VERSION 5.8 ;
BUSBITCHARS "[]" ;
DIVIDERCHAR "/" ;
UNITS DISTANCE MICRONS 2000 ;

# Standard Cell Library - Base AT (Advanced Threshold)
# Technology: tcbn07 (7nm node), BWP300H8P64PD (Back-end), LVT (Low Vt)

# Inverter
MACRO INVX1BWP300H8P64PDLVT
  CLASS CORE ;
  ORIGIN 0.0 0.0 ;
  SIZE 0.3 BY 0.3 ;
  SYMMETRY X Y ;
  PIN A
    DIRECTION INPUT ;
    USE SIGNAL ;
    PORT
      LAYER M1 ;
      RECT 0.0 0.1 0.1 0.2 ;
    END
  END A
  PIN Y
    DIRECTION OUTPUT ;
    USE SIGNAL ;
    PORT
      LAYER M1 ;
      RECT 0.2 0.1 0.3 0.2 ;
    END
  END Y
END INVX1BWP300H8P64PDLVT

# Buffers
MACRO BUFFD1BWP300H8P64PDLVT
  CLASS CORE ;
  ORIGIN 0.0 0.0 ;
  SIZE 0.45 BY 0.3 ;
  SYMMETRY X Y ;
  PIN A
    DIRECTION INPUT ;
    USE SIGNAL ;
    PORT
      LAYER M1 ;
      RECT 0.0 0.1 0.1 0.2 ;
    END
  END A
  PIN Y
    DIRECTION OUTPUT ;
    USE SIGNAL ;
    PORT
      LAYER M1 ;
      RECT 0.35 0.1 0.45 0.2 ;
    END
  END Y
END BUFFD1BWP300H8P64PDLVT

MACRO BUFFD2BWP300H8P64PDLVT
  CLASS CORE ;
  ORIGIN 0.0 0.0 ;
  SIZE 0.6 BY 0.3 ;
  SYMMETRY X Y ;
  PIN A
    DIRECTION INPUT ;
    USE SIGNAL ;
    PORT
      LAYER M1 ;
      RECT 0.0 0.1 0.1 0.2 ;
    END
  END A
  PIN Y
    DIRECTION OUTPUT ;
    USE SIGNAL ;
    PORT
      LAYER M1 ;
      RECT 0.5 0.1 0.6 0.2 ;
    END
  END Y
END BUFFD2BWP300H8P64PDLVT

MACRO BUFFD3BWP300H8P64PDLVT
  CLASS CORE ;
  ORIGIN 0.0 0.0 ;
  SIZE 0.75 BY 0.3 ;
  SYMMETRY X Y ;
  PIN A
    DIRECTION INPUT ;
    USE SIGNAL ;
    PORT
      LAYER M1 ;
      RECT 0.0 0.1 0.1 0.2 ;
    END
  END A
  PIN Y
    DIRECTION OUTPUT ;
    USE SIGNAL ;
    PORT
      LAYER M1 ;
      RECT 0.65 0.1 0.75 0.2 ;
    END
  END Y
END BUFFD3BWP300H8P64PDLVT

MACRO BUFFD4BWP300H8P64PDLVT
  CLASS CORE ;
  ORIGIN 0.0 0.0 ;
  SIZE 0.9 BY 0.3 ;
  SYMMETRY X Y ;
  PIN A
    DIRECTION INPUT ;
    USE SIGNAL ;
    PORT
      LAYER M1 ;
      RECT 0.0 0.1 0.1 0.2 ;
    END
  END A
  PIN Y
    DIRECTION OUTPUT ;
    USE SIGNAL ;
    PORT
      LAYER M1 ;
      RECT 0.8 0.1 0.9 0.2 ;
    END
  END Y
END BUFFD4BWP300H8P64PDLVT

MACRO BUFFD6BWP300H8P64PDLVT
  CLASS CORE ;
  ORIGIN 0.0 0.0 ;
  SIZE 1.2 BY 0.3 ;
  SYMMETRY X Y ;
  PIN A
    DIRECTION INPUT ;
    USE SIGNAL ;
    PORT
      LAYER M1 ;
      RECT 0.0 0.1 0.1 0.2 ;
    END
  END A
  PIN Y
    DIRECTION OUTPUT ;
    USE SIGNAL ;
    PORT
      LAYER M1 ;
      RECT 1.1 0.1 1.2 0.2 ;
    END
  END Y
END BUFFD6BWP300H8P64PDLVT

MACRO BUFFD8BWP300H8P64PDLVT
  CLASS CORE ;
  ORIGIN 0.0 0.0 ;
  SIZE 1.5 BY 0.3 ;
  SYMMETRY X Y ;
  PIN A
    DIRECTION INPUT ;
    USE SIGNAL ;
    PORT
      LAYER M1 ;
      RECT 0.0 0.1 0.1 0.2 ;
    END
  END A
  PIN Y
    DIRECTION OUTPUT ;
    USE SIGNAL ;
    PORT
      LAYER M1 ;
      RECT 1.4 0.1 1.5 0.2 ;
    END
  END Y
END BUFFD8BWP300H8P64PDLVT

# AND gates
MACRO AN2D1BWP300H8P64PDLVT
  CLASS CORE ;
  ORIGIN 0.0 0.0 ;
  SIZE 0.45 BY 0.3 ;
  SYMMETRY X Y ;
  PIN A
    DIRECTION INPUT ;
    USE SIGNAL ;
    PORT
      LAYER M1 ;
      RECT 0.0 0.1 0.1 0.2 ;
    END
  END A
  PIN B
    DIRECTION INPUT ;
    USE SIGNAL ;
    PORT
      LAYER M1 ;
      RECT 0.15 0.1 0.25 0.2 ;
    END
  END B
  PIN Y
    DIRECTION OUTPUT ;
    USE SIGNAL ;
    PORT
      LAYER M1 ;
      RECT 0.35 0.1 0.45 0.2 ;
    END
  END Y
END AN2D1BWP300H8P64PDLVT

MACRO AN2D2BWP300H8P64PDLVT
  CLASS CORE ;
  ORIGIN 0.0 0.0 ;
  SIZE 0.45 BY 0.3 ;
  SYMMETRY X Y ;
  PIN A
    DIRECTION INPUT ;
    USE SIGNAL ;
    PORT
      LAYER M1 ;
      RECT 0.0 0.1 0.1 0.2 ;
    END
  END A
  PIN B
    DIRECTION INPUT ;
    USE SIGNAL ;
    PORT
      LAYER M1 ;
      RECT 0.15 0.1 0.25 0.2 ;
    END
  END B
  PIN Y
    DIRECTION OUTPUT ;
    USE SIGNAL ;
    PORT
      LAYER M1 ;
      RECT 0.35 0.1 0.45 0.2 ;
    END
  END Y
END AN2D2BWP300H8P64PDLVT

MACRO AN2D3BWP300H8P64PDLVT
  CLASS CORE ;
  ORIGIN 0.0 0.0 ;
  SIZE 0.45 BY 0.3 ;
  SYMMETRY X Y ;
  PIN A
    DIRECTION INPUT ;
    USE SIGNAL ;
    PORT
      LAYER M1 ;
      RECT 0.0 0.1 0.1 0.2 ;
    END
  END A
  PIN B
    DIRECTION INPUT ;
    USE SIGNAL ;
    PORT
      LAYER M1 ;
      RECT 0.15 0.1 0.25 0.2 ;
    END
  END B
  PIN Y
    DIRECTION OUTPUT ;
    USE SIGNAL ;
    PORT
      LAYER M1 ;
      RECT 0.35 0.1 0.45 0.2 ;
    END
  END Y
END AN2D3BWP300H8P64PDLVT

MACRO AN2D4BWP300H8P64PDLVT
  CLASS CORE ;
  ORIGIN 0.0 0.0 ;
  SIZE 0.6 BY 0.3 ;
  SYMMETRY X Y ;
  PIN A
    DIRECTION INPUT ;
    USE SIGNAL ;
    PORT
      LAYER M1 ;
      RECT 0.0 0.1 0.1 0.2 ;
    END
  END A
  PIN B
    DIRECTION INPUT ;
    USE SIGNAL ;
    PORT
      LAYER M1 ;
      RECT 0.2 0.1 0.3 0.2 ;
    END
  END B
  PIN Y
    DIRECTION OUTPUT ;
    USE SIGNAL ;
    PORT
      LAYER M1 ;
      RECT 0.45 0.1 0.6 0.2 ;
    END
  END Y
END AN2D4BWP300H8P64PDLVT

# OR gates
MACRO OR2D1BWP300H8P64PDLVT
  CLASS CORE ;
  ORIGIN 0.0 0.0 ;
  SIZE 0.45 BY 0.3 ;
  SYMMETRY X Y ;
  PIN A
    DIRECTION INPUT ;
    USE SIGNAL ;
    PORT
      LAYER M1 ;
      RECT 0.0 0.1 0.1 0.2 ;
    END
  END A
  PIN B
    DIRECTION INPUT ;
    USE SIGNAL ;
    PORT
      LAYER M1 ;
      RECT 0.15 0.1 0.25 0.2 ;
    END
  END B
  PIN Y
    DIRECTION OUTPUT ;
    USE SIGNAL ;
    PORT
      LAYER M1 ;
      RECT 0.35 0.1 0.45 0.2 ;
    END
  END Y
END OR2D1BWP300H8P64PDLVT

MACRO OR2D2BWP300H8P64PDLVT
  CLASS CORE ;
  ORIGIN 0.0 0.0 ;
  SIZE 0.45 BY 0.3 ;
  SYMMETRY X Y ;
  PIN A
    DIRECTION INPUT ;
    USE SIGNAL ;
    PORT
      LAYER M1 ;
      RECT 0.0 0.1 0.1 0.2 ;
    END
  END A
  PIN B
    DIRECTION INPUT ;
    USE SIGNAL ;
    PORT
      LAYER M1 ;
      RECT 0.15 0.1 0.25 0.2 ;
    END
  END B
  PIN Y
    DIRECTION OUTPUT ;
    USE SIGNAL ;
    PORT
      LAYER M1 ;
      RECT 0.35 0.1 0.45 0.2 ;
    END
  END Y
END OR2D2BWP300H8P64PDLVT

# NAND gates
MACRO NAND2D1BWP300H8P64PDLVT
  CLASS CORE ;
  ORIGIN 0.0 0.0 ;
  SIZE 0.45 BY 0.3 ;
  SYMMETRY X Y ;
  PIN A
    DIRECTION INPUT ;
    USE SIGNAL ;
    PORT
      LAYER M1 ;
      RECT 0.0 0.1 0.1 0.2 ;
    END
  END A
  PIN B
    DIRECTION INPUT ;
    USE SIGNAL ;
    PORT
      LAYER M1 ;
      RECT 0.15 0.1 0.25 0.2 ;
    END
  END B
  PIN Y
    DIRECTION OUTPUT ;
    USE SIGNAL ;
    PORT
      LAYER M1 ;
      RECT 0.35 0.1 0.45 0.2 ;
    END
  END Y
END NAND2D1BWP300H8P64PDLVT

# NOR gates
MACRO NOR2D1BWP300H8P64PDLVT
  CLASS CORE ;
  ORIGIN 0.0 0.0 ;
  SIZE 0.45 BY 0.3 ;
  SYMMETRY X Y ;
  PIN A
    DIRECTION INPUT ;
    USE SIGNAL ;
    PORT
      LAYER M1 ;
      RECT 0.0 0.1 0.1 0.2 ;
    END
  END A
  PIN B
    DIRECTION INPUT ;
    USE SIGNAL ;
    PORT
      LAYER M1 ;
      RECT 0.15 0.1 0.25 0.2 ;
    END
  END B
  PIN Y
    DIRECTION OUTPUT ;
    USE SIGNAL ;
    PORT
      LAYER M1 ;
      RECT 0.35 0.1 0.45 0.2 ;
    END
  END Y
END NOR2D1BWP300H8P64PDLVT

# XOR gates
MACRO XOR2D1BWP300H8P64PDLVT
  CLASS CORE ;
  ORIGIN 0.0 0.0 ;
  SIZE 0.45 BY 0.3 ;
  SYMMETRY X Y ;
  PIN A
    DIRECTION INPUT ;
    USE SIGNAL ;
    PORT
      LAYER M1 ;
      RECT 0.0 0.1 0.1 0.2 ;
    END
  END A
  PIN B
    DIRECTION INPUT ;
    USE SIGNAL ;
    PORT
      LAYER M1 ;
      RECT 0.15 0.1 0.25 0.2 ;
    END
  END B
  PIN Y
    DIRECTION OUTPUT ;
    USE SIGNAL ;
    PORT
      LAYER M1 ;
      RECT 0.35 0.1 0.45 0.2 ;
    END
  END Y
END XOR2D1BWP300H8P64PDLVT

# 3-input gates
MACRO AN3D1BWP300H8P64PDLVT
  CLASS CORE ;
  ORIGIN 0.0 0.0 ;
  SIZE 0.6 BY 0.3 ;
  SYMMETRY X Y ;
  PIN A
    DIRECTION INPUT ;
    USE SIGNAL ;
    PORT
      LAYER M1 ;
      RECT 0.0 0.1 0.1 0.2 ;
    END
  END A
  PIN B
    DIRECTION INPUT ;
    USE SIGNAL ;
    PORT
      LAYER M1 ;
      RECT 0.2 0.1 0.3 0.2 ;
    END
  END B
  PIN C
    DIRECTION INPUT ;
    USE SIGNAL ;
    PORT
      LAYER M1 ;
      RECT 0.4 0.1 0.5 0.2 ;
    END
  END C
  PIN Y
    DIRECTION OUTPUT ;
    USE SIGNAL ;
    PORT
      LAYER M1 ;
      RECT 0.5 0.1 0.6 0.2 ;
    END
  END Y
END AN3D1BWP300H8P64PDLVT

# Flip-flops
MACRO CKLNQD1BWP300H8P64PDLVT
  CLASS CORE ;
  ORIGIN 0.0 0.0 ;
  SIZE 0.6 BY 0.6 ;
  SYMMETRY X Y ;
  PIN CP
    DIRECTION INPUT ;
    USE SIGNAL ;
    PORT
      LAYER M1 ;
      RECT 0.0 0.4 0.1 0.5 ;
    END
  END CP
  PIN E
    DIRECTION INPUT ;
    USE SIGNAL ;
    PORT
      LAYER M1 ;
      RECT 0.0 0.2 0.1 0.3 ;
    END
  END E
  PIN TE
    DIRECTION INPUT ;
    USE SIGNAL ;
    PORT
      LAYER M1 ;
      RECT 0.0 0.1 0.1 0.2 ;
    END
  END TE
  PIN Q
    DIRECTION OUTPUT ;
    USE SIGNAL ;
    PORT
      LAYER M1 ;
      RECT 0.5 0.4 0.6 0.5 ;
    END
  END Q
END CKLNQD1BWP300H8P64PDLVT

# AOI gates
MACRO AOI21D1BWP300H8P64PDLVT
  CLASS CORE ;
  ORIGIN 0.0 0.0 ;
  SIZE 0.75 BY 0.3 ;
  SYMMETRY X Y ;
  PIN A
    DIRECTION INPUT ;
    USE SIGNAL ;
    PORT
      LAYER M1 ;
      RECT 0.0 0.1 0.1 0.2 ;
    END
  END A
  PIN B
    DIRECTION INPUT ;
    USE SIGNAL ;
    PORT
      LAYER M1 ;
      RECT 0.15 0.1 0.25 0.2 ;
    END
  END B
  PIN C
    DIRECTION INPUT ;
    USE SIGNAL ;
    PORT
      LAYER M1 ;
      RECT 0.3 0.1 0.4 0.2 ;
    END
  END C
  PIN Y
    DIRECTION OUTPUT ;
    USE SIGNAL ;
    PORT
      LAYER M1 ;
      RECT 0.6 0.1 0.75 0.2 ;
    END
  END Y
END AOI21D1BWP300H8P64PDLVT

MACRO AOI22D1BWP300H8P64PDLVT
  CLASS CORE ;
  ORIGIN 0.0 0.0 ;
  SIZE 0.9 BY 0.3 ;
  SYMMETRY X Y ;
  PIN A
    DIRECTION INPUT ;
    USE SIGNAL ;
    PORT
      LAYER M1 ;
      RECT 0.0 0.1 0.1 0.2 ;
    END
  END A
  PIN B
    DIRECTION INPUT ;
    USE SIGNAL ;
    PORT
      LAYER M1 ;
      RECT 0.2 0.1 0.3 0.2 ;
    END
  END B
  PIN C
    DIRECTION INPUT ;
    USE SIGNAL ;
    PORT
      LAYER M1 ;
      RECT 0.4 0.1 0.5 0.2 ;
    END
  END C
  PIN D
    DIRECTION INPUT ;
    USE SIGNAL ;
    PORT
      LAYER M1 ;
      RECT 0.6 0.1 0.7 0.2 ;
    END
  END D
  PIN Y
    DIRECTION OUTPUT ;
    USE SIGNAL ;
    PORT
      LAYER M1 ;
      RECT 0.8 0.1 0.9 0.2 ;
    END
  END Y
END AOI22D1BWP300H8P64PDLVT

# Layers
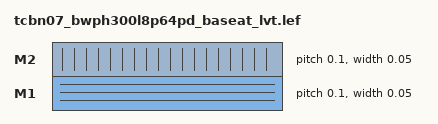
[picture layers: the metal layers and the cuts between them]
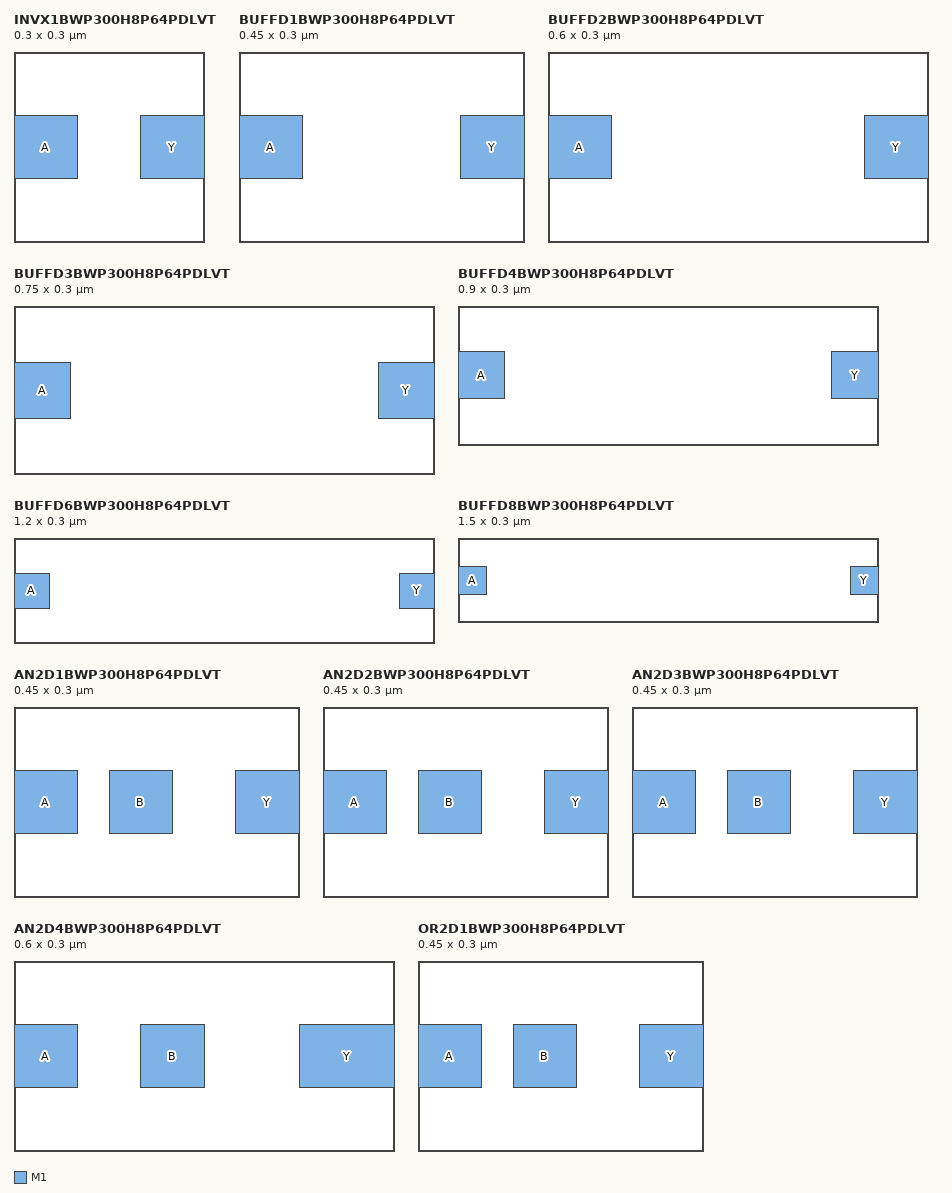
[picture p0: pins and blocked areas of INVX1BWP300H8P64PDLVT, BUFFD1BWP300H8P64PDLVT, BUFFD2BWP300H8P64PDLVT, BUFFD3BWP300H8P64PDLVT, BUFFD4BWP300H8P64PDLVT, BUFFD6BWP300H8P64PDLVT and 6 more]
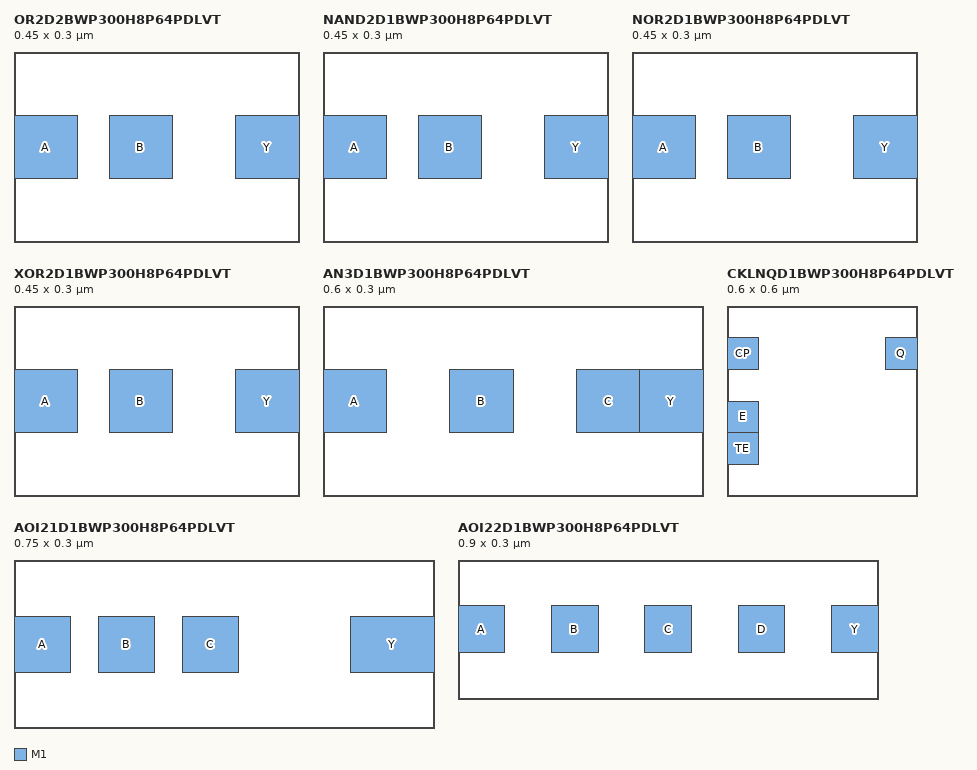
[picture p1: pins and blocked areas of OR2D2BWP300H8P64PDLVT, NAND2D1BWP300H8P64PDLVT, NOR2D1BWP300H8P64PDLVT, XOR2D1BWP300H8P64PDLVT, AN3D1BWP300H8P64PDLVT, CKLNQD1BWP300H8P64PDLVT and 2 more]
LAYER M1
  TYPE ROUTING ;
  DIRECTION HORIZONTAL ;
  PITCH 0.1 ;
  WIDTH 0.05 ;
END M1

LAYER M2
  TYPE ROUTING ;
  DIRECTION VERTICAL ;
  PITCH 0.1 ;
  WIDTH 0.05 ;
END M2

SITE CORE
  CLASS CORE ;
  SIZE 0.3 BY 0.3 ;
  SYMMETRY X Y ;
END CORE

END LIBRARY
